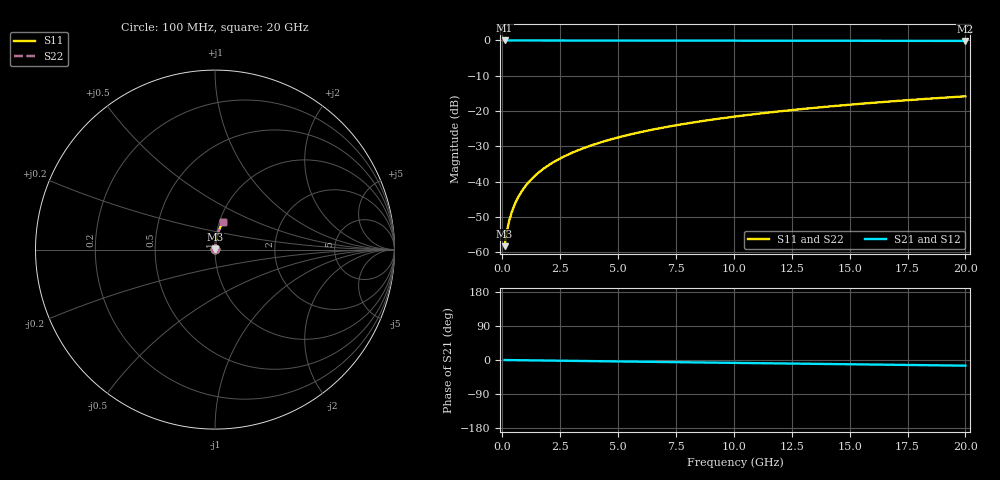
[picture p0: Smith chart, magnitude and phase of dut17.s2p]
! Touchstone file exported from HFSS 2026.1.0
!  File:  C:/ffzhzh/LocalFiles/Ansys_Project_Files/temp_test_TMRDL_17_1782907137_8056.aedt
!  Generated:  08:00:10 PM Jul  1, 2026
!  Design:  TMRDL
!  Project:  temp_test_TMRDL_17_1782907137_8056
! Variables:
!  h_bsmrdl = 2um
!  h_ox = 20um
!  h_rdl = 5um
!  h_sub = 80um
!  h_tmrdl = 3.8um
!  h_tsv = 80um
!  h_via = 3um
!  l_bsmrdl = 300um
!  l_sub = 562.08um
!  l_tmrdl = 162.08um
!  m_sub = 200um
!  pitch = 59um
!  r_tsv = 6um
!  s_tmrdl = 10um
!  w_bsmrdl = 18um
!  w_sub = 500um
!  w_tmrdl = 25.96um
!  x_tsv_center1 = 175.06um
!  x_tsv_center2 = 493.06um
!  x_tsv_center3 = 681.1um
!  x_tsv_center4 = 999.1um
!  x_tsv_center5 = 1187.14um
!  x_tsv_center6 = 1505.14um
# GHz S MA R 50.000000
! Terminal data exported
! Port[1] = TM_RDL1_1_T1
! Port[2] = TM_RDL1_1_T2
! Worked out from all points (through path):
!   200 points, 100 MHz to 20 GHz, reference 50 ohm
!   highest |S21| = -0.01 dB at 100 MHz (marker M1); lowest = -0.1 dB at 20 GHz (marker M2)
!   group delay of S21, straight-line fit = 2.07 ps
!   lowest |S11| = -58.3 dB at 100 MHz (marker M3), VSWR 1.00, Z = 50.1 + j0.0916 ohm
!   |S11| at or under -10 dB: start of sweep to end of sweep
!   |S22| runs from -58.3 to -15.8 dB; largest |S21 - S12| = 2e-15
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0.1  0.001219 48.6  0.9992 -0.1  0.9992 -0.1  0.001219 48.6
! Gamma 0 0 0 0
! Port Impedance 50 0 50 0
0.2  0.001992 64.6  0.9992 -0.2  0.9992 -0.2  0.001992 64.6
0.3  0.002808 71.3  0.9991 -0.2  0.9991 -0.2  0.002808 71.3
0.4  0.003631 75.0  0.9991 -0.3  0.9991 -0.3  0.003631 75.0
0.5  0.004458 77.4  0.999 -0.4  0.999 -0.4  0.004458 77.4
0.7  0.006125 80.3  0.999 -0.5  0.999 -0.5  0.006125 80.3
0.8  0.006963 81.2  0.999 -0.6  0.999 -0.6  0.006963 81.2
1  0.008646 82.5  0.9989 -0.8  0.9989 -0.8  0.008646 82.5
1.2  0.01033 83.4  0.9989 -0.9  0.9989 -0.9  0.01033 83.4
1.4  0.01202 83.9  0.9989 -1.1  0.9989 -1.1  0.01202 83.9
1.7  0.01456 84.4  0.9988 -1.3  0.9988 -1.3  0.01456 84.4
2  0.0171 84.7  0.9987 -1.5  0.9987 -1.5  0.0171 84.7
2.7  0.02301 84.9  0.9985 -2.1  0.9985 -2.1  0.02301 84.9
3.5  0.02974 84.7  0.9982 -2.7  0.9982 -2.7  0.02974 84.7
4.2  0.0356 84.4  0.9979 -3.2  0.9979 -3.2  0.0356 84.4
5  0.04226 84.0  0.9975 -3.8  0.9975 -3.8  0.04226 84.0
6.8  0.05711 82.8  0.9964 -5.2  0.9964 -5.2  0.05711 82.8
8.3  0.06937 81.8  0.9953 -6.3  0.9953 -6.3  0.06937 81.8
10.1  0.08395 80.6  0.9939 -7.6  0.9939 -7.6  0.08395 80.6
13.4  0.1104 78.4  0.9909 -10.1  0.9909 -10.1  0.1104 78.4
16.7  0.1363 76.1  0.9873 -12.5  0.9873 -12.5  0.1363 76.1
20  0.1617 73.8  0.9832 -14.9  0.9832 -14.9  0.1617 73.8
